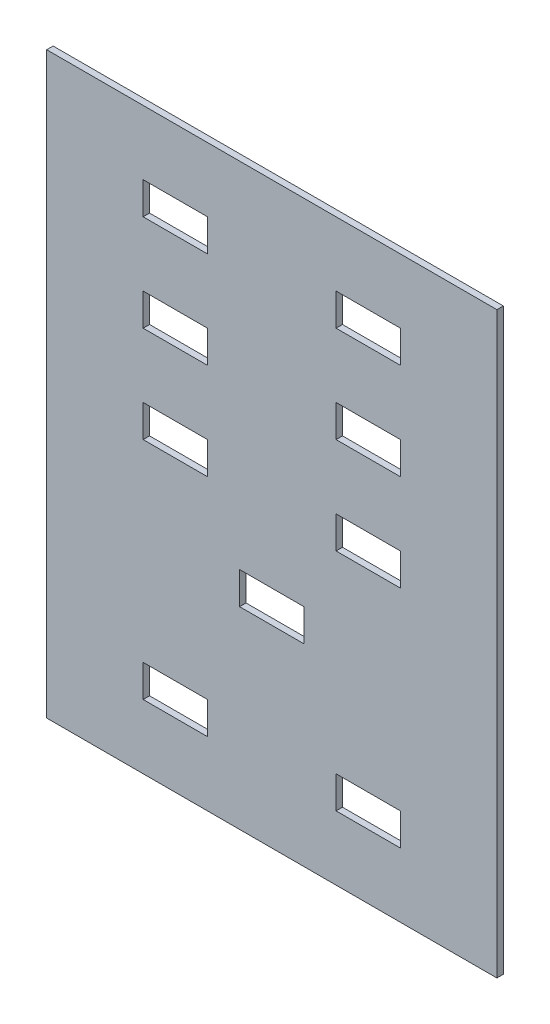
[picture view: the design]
ISO-10303-21;
HEADER;
FILE_DESCRIPTION(('STEP AP214'),'2;1');
FILE_NAME('part.step','',(''),(''),'','','');
FILE_SCHEMA(('AUTOMOTIVE_DESIGN { 1 0 10303 214 1 1 1 1 }'));
ENDSEC;
DATA;
#1=APPLICATION_CONTEXT('core data for automotive mechanical design processes');
#2=APPLICATION_PROTOCOL_DEFINITION('international standard','automotive_design',2000,#1);
#3=PRODUCT_CONTEXT('',#1,'mechanical');
#4=PRODUCT('Part','Part','',(#3));
#5=PRODUCT_RELATED_PRODUCT_CATEGORY('part','',(#4));
#6=PRODUCT_DEFINITION_FORMATION('','',#4);
#7=PRODUCT_DEFINITION_CONTEXT('part definition',#1,'design');
#8=PRODUCT_DEFINITION('design','',#6,#7);
#9=PRODUCT_DEFINITION_SHAPE('','',#8);
#10=(LENGTH_UNIT() NAMED_UNIT(*) SI_UNIT(.MILLI.,.METRE.));
#11=(NAMED_UNIT(*) PLANE_ANGLE_UNIT() SI_UNIT($,.RADIAN.));
#12=(NAMED_UNIT(*) SI_UNIT($,.STERADIAN.) SOLID_ANGLE_UNIT());
#13=UNCERTAINTY_MEASURE_WITH_UNIT(LENGTH_MEASURE(1.E-05),#10,'distance_accuracy_value','');
#14=(GEOMETRIC_REPRESENTATION_CONTEXT(3) GLOBAL_UNCERTAINTY_ASSIGNED_CONTEXT((#13)) GLOBAL_UNIT_ASSIGNED_CONTEXT((#10,
#11,#12)) REPRESENTATION_CONTEXT('',''));
#15=CARTESIAN_POINT('',(0.,0.,0.));
#16=DIRECTION('',(0.,0.,1.));
#17=DIRECTION('',(1.,0.,0.));
#18=AXIS2_PLACEMENT_3D('',#15,#16,#17);
#19=CARTESIAN_POINT('',(0.,0.,5.));
#20=DIRECTION('',(1.,0.,0.));
#21=DIRECTION('',(0.,0.,-1.));
#22=AXIS2_PLACEMENT_3D('',#19,#20,#21);
#23=PLANE('',#22);
#24=DIRECTION('',(0.,-1.,0.));
#25=VECTOR('',#24,1.);
#26=CARTESIAN_POINT('',(0.,0.,0.));
#27=LINE('',#26,#25);
#28=CARTESIAN_POINT('',(0.,450.,0.));
#29=VERTEX_POINT('',#28);
#30=CARTESIAN_POINT('',(0.,0.,0.));
#31=VERTEX_POINT('',#30);
#32=EDGE_CURVE('E576',#29,#31,#27,.T.);
#33=ORIENTED_EDGE('',*,*,#32,.T.);
#34=DIRECTION('',(0.,0.,-1.));
#35=VECTOR('',#34,1.);
#36=CARTESIAN_POINT('',(0.,0.,5.));
#37=LINE('',#36,#35);
#38=CARTESIAN_POINT('',(0.,0.,5.));
#39=VERTEX_POINT('',#38);
#40=EDGE_CURVE('E11',#39,#31,#37,.T.);
#41=ORIENTED_EDGE('',*,*,#40,.F.);
#42=DIRECTION('',(0.,-1.,0.));
#43=VECTOR('',#42,1.);
#44=CARTESIAN_POINT('',(0.,0.,5.));
#45=LINE('',#44,#43);
#46=CARTESIAN_POINT('',(0.,450.,5.));
#47=VERTEX_POINT('',#46);
#48=EDGE_CURVE('E583',#47,#39,#45,.T.);
#49=ORIENTED_EDGE('',*,*,#48,.F.);
#50=DIRECTION('',(0.,0.,-1.));
#51=VECTOR('',#50,1.);
#52=CARTESIAN_POINT('',(0.,450.,5.));
#53=LINE('',#52,#51);
#54=EDGE_CURVE('E593',#47,#29,#53,.T.);
#55=ORIENTED_EDGE('',*,*,#54,.T.);
#56=EDGE_LOOP('',(#33,#41,#49,#55));
#57=FACE_BOUND('',#56,.T.);
#58=ADVANCED_FACE('F34',(#57),#23,.F.);
#59=CARTESIAN_POINT('',(0.,0.,5.));
#60=DIRECTION('',(0.,1.,0.));
#61=DIRECTION('',(0.,0.,1.));
#62=AXIS2_PLACEMENT_3D('',#59,#60,#61);
#63=PLANE('',#62);
#64=DIRECTION('',(1.,0.,0.));
#65=VECTOR('',#64,1.);
#66=CARTESIAN_POINT('',(0.,0.,0.));
#67=LINE('',#66,#65);
#68=CARTESIAN_POINT('',(350.,0.,0.));
#69=VERTEX_POINT('',#68);
#70=EDGE_CURVE('E596',#31,#69,#67,.T.);
#71=ORIENTED_EDGE('',*,*,#70,.T.);
#72=DIRECTION('',(0.,0.,-1.));
#73=VECTOR('',#72,1.);
#74=CARTESIAN_POINT('',(350.,0.,5.));
#75=LINE('',#74,#73);
#76=CARTESIAN_POINT('',(350.,0.,5.));
#77=VERTEX_POINT('',#76);
#78=EDGE_CURVE('E41',#77,#69,#75,.T.);
#79=ORIENTED_EDGE('',*,*,#78,.F.);
#80=DIRECTION('',(1.,0.,0.));
#81=VECTOR('',#80,1.);
#82=CARTESIAN_POINT('',(0.,0.,5.));
#83=LINE('',#82,#81);
#84=EDGE_CURVE('E586',#39,#77,#83,.T.);
#85=ORIENTED_EDGE('',*,*,#84,.F.);
#86=ORIENTED_EDGE('',*,*,#40,.T.);
#87=EDGE_LOOP('',(#71,#79,#85,#86));
#88=FACE_BOUND('',#87,.T.);
#89=ADVANCED_FACE('F625',(#88),#63,.F.);
#90=CARTESIAN_POINT('',(350.,0.,5.));
#91=DIRECTION('',(-1.,0.,0.));
#92=DIRECTION('',(0.,0.,1.));
#93=AXIS2_PLACEMENT_3D('',#90,#91,#92);
#94=PLANE('',#93);
#95=DIRECTION('',(0.,1.,0.));
#96=VECTOR('',#95,1.);
#97=CARTESIAN_POINT('',(350.,0.,0.));
#98=LINE('',#97,#96);
#99=CARTESIAN_POINT('',(350.,450.,0.));
#100=VERTEX_POINT('',#99);
#101=EDGE_CURVE('E598',#69,#100,#98,.T.);
#102=ORIENTED_EDGE('',*,*,#101,.T.);
#103=DIRECTION('',(0.,0.,-1.));
#104=VECTOR('',#103,1.);
#105=CARTESIAN_POINT('',(350.,450.,5.));
#106=LINE('',#105,#104);
#107=CARTESIAN_POINT('',(350.,450.,5.));
#108=VERTEX_POINT('',#107);
#109=EDGE_CURVE('E603',#108,#100,#106,.T.);
#110=ORIENTED_EDGE('',*,*,#109,.F.);
#111=DIRECTION('',(0.,1.,0.));
#112=VECTOR('',#111,1.);
#113=CARTESIAN_POINT('',(350.,0.,5.));
#114=LINE('',#113,#112);
#115=EDGE_CURVE('E589',#77,#108,#114,.T.);
#116=ORIENTED_EDGE('',*,*,#115,.F.);
#117=ORIENTED_EDGE('',*,*,#78,.T.);
#118=EDGE_LOOP('',(#102,#110,#116,#117));
#119=FACE_BOUND('',#118,.T.);
#120=ADVANCED_FACE('F610',(#119),#94,.F.);
#121=CARTESIAN_POINT('',(0.,450.,5.));
#122=DIRECTION('',(0.,-1.,0.));
#123=DIRECTION('',(0.,0.,-1.));
#124=AXIS2_PLACEMENT_3D('',#121,#122,#123);
#125=PLANE('',#124);
#126=DIRECTION('',(-1.,0.,0.));
#127=VECTOR('',#126,1.);
#128=CARTESIAN_POINT('',(0.,450.,0.));
#129=LINE('',#128,#127);
#130=EDGE_CURVE('E587',#100,#29,#129,.T.);
#131=ORIENTED_EDGE('',*,*,#130,.T.);
#132=ORIENTED_EDGE('',*,*,#54,.F.);
#133=DIRECTION('',(-1.,0.,0.));
#134=VECTOR('',#133,1.);
#135=CARTESIAN_POINT('',(0.,450.,5.));
#136=LINE('',#135,#134);
#137=EDGE_CURVE('E591',#108,#47,#136,.T.);
#138=ORIENTED_EDGE('',*,*,#137,.F.);
#139=ORIENTED_EDGE('',*,*,#109,.T.);
#140=EDGE_LOOP('',(#131,#132,#138,#139));
#141=FACE_BOUND('',#140,.T.);
#142=ADVANCED_FACE('F618',(#141),#125,.F.);
#143=CARTESIAN_POINT('',(0.,0.,5.));
#144=DIRECTION('',(0.,0.,-1.));
#145=DIRECTION('',(-1.,0.,0.));
#146=AXIS2_PLACEMENT_3D('',#143,#144,#145);
#147=PLANE('',#146);
#148=DIRECTION('',(-1.,0.,0.));
#149=VECTOR('',#148,1.);
#150=CARTESIAN_POINT('',(225.,75.,5.));
#151=LINE('',#150,#149);
#152=CARTESIAN_POINT('',(275.,75.,5.));
#153=VERTEX_POINT('',#152);
#154=CARTESIAN_POINT('',(225.,75.,5.));
#155=VERTEX_POINT('',#154);
#156=EDGE_CURVE('E317',#153,#155,#151,.T.);
#157=ORIENTED_EDGE('',*,*,#156,.F.);
#158=DIRECTION('',(0.,1.,0.));
#159=VECTOR('',#158,1.);
#160=CARTESIAN_POINT('',(275.,49.9999999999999,5.));
#161=LINE('',#160,#159);
#162=CARTESIAN_POINT('',(275.,49.9999999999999,5.));
#163=VERTEX_POINT('',#162);
#164=EDGE_CURVE('E48',#163,#153,#161,.T.);
#165=ORIENTED_EDGE('',*,*,#164,.F.);
#166=DIRECTION('',(1.,0.,0.));
#167=VECTOR('',#166,1.);
#168=CARTESIAN_POINT('',(225.,49.9999999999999,5.));
#169=LINE('',#168,#167);
#170=CARTESIAN_POINT('',(225.,49.9999999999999,5.));
#171=VERTEX_POINT('',#170);
#172=EDGE_CURVE('E308',#171,#163,#169,.T.);
#173=ORIENTED_EDGE('',*,*,#172,.F.);
#174=DIRECTION('',(0.,-1.,0.));
#175=VECTOR('',#174,1.);
#176=CARTESIAN_POINT('',(225.,49.9999999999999,5.));
#177=LINE('',#176,#175);
#178=EDGE_CURVE('E311',#155,#171,#177,.T.);
#179=ORIENTED_EDGE('',*,*,#178,.F.);
#180=EDGE_LOOP('',(#157,#165,#173,#179));
#181=FACE_BOUND('',#180,.T.);
#182=DIRECTION('',(-1.,0.,0.));
#183=VECTOR('',#182,1.);
#184=CARTESIAN_POINT('',(75.0000000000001,75.,5.));
#185=LINE('',#184,#183);
#186=CARTESIAN_POINT('',(125.,75.,5.));
#187=VERTEX_POINT('',#186);
#188=CARTESIAN_POINT('',(75.0000000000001,75.,5.));
#189=VERTEX_POINT('',#188);
#190=EDGE_CURVE('E342',#187,#189,#185,.T.);
#191=ORIENTED_EDGE('',*,*,#190,.F.);
#192=DIRECTION('',(0.,1.,0.));
#193=VECTOR('',#192,1.);
#194=CARTESIAN_POINT('',(125.,49.9999999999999,5.));
#195=LINE('',#194,#193);
#196=CARTESIAN_POINT('',(125.,49.9999999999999,5.));
#197=VERTEX_POINT('',#196);
#198=EDGE_CURVE('E323',#197,#187,#195,.T.);
#199=ORIENTED_EDGE('',*,*,#198,.F.);
#200=DIRECTION('',(1.,0.,0.));
#201=VECTOR('',#200,1.);
#202=CARTESIAN_POINT('',(75.0000000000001,49.9999999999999,5.));
#203=LINE('',#202,#201);
#204=CARTESIAN_POINT('',(75.0000000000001,49.9999999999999,5.));
#205=VERTEX_POINT('',#204);
#206=EDGE_CURVE('E331',#205,#197,#203,.T.);
#207=ORIENTED_EDGE('',*,*,#206,.F.);
#208=DIRECTION('',(0.,-1.,0.));
#209=VECTOR('',#208,1.);
#210=CARTESIAN_POINT('',(75.0000000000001,49.9999999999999,5.));
#211=LINE('',#210,#209);
#212=EDGE_CURVE('E345',#189,#205,#211,.T.);
#213=ORIENTED_EDGE('',*,*,#212,.F.);
#214=EDGE_LOOP('',(#191,#199,#207,#213));
#215=FACE_BOUND('',#214,.T.);
#216=DIRECTION('',(-1.,0.,0.));
#217=VECTOR('',#216,1.);
#218=CARTESIAN_POINT('',(150.,175.,5.));
#219=LINE('',#218,#217);
#220=CARTESIAN_POINT('',(200.,175.,5.));
#221=VERTEX_POINT('',#220);
#222=CARTESIAN_POINT('',(150.,175.,5.));
#223=VERTEX_POINT('',#222);
#224=EDGE_CURVE('E374',#221,#223,#219,.T.);
#225=ORIENTED_EDGE('',*,*,#224,.F.);
#226=DIRECTION('',(0.,1.,0.));
#227=VECTOR('',#226,1.);
#228=CARTESIAN_POINT('',(200.,150.,5.));
#229=LINE('',#228,#227);
#230=CARTESIAN_POINT('',(200.,150.,5.));
#231=VERTEX_POINT('',#230);
#232=EDGE_CURVE('E352',#231,#221,#229,.T.);
#233=ORIENTED_EDGE('',*,*,#232,.F.);
#234=DIRECTION('',(1.,0.,0.));
#235=VECTOR('',#234,1.);
#236=CARTESIAN_POINT('',(150.,150.,5.));
#237=LINE('',#236,#235);
#238=CARTESIAN_POINT('',(150.,150.,5.));
#239=VERTEX_POINT('',#238);
#240=EDGE_CURVE('E363',#239,#231,#237,.T.);
#241=ORIENTED_EDGE('',*,*,#240,.F.);
#242=DIRECTION('',(0.,-1.,0.));
#243=VECTOR('',#242,1.);
#244=CARTESIAN_POINT('',(150.,150.,5.));
#245=LINE('',#244,#243);
#246=EDGE_CURVE('E377',#223,#239,#245,.T.);
#247=ORIENTED_EDGE('',*,*,#246,.F.);
#248=EDGE_LOOP('',(#225,#233,#241,#247));
#249=FACE_BOUND('',#248,.T.);
#250=DIRECTION('',(-1.,0.,0.));
#251=VECTOR('',#250,1.);
#252=CARTESIAN_POINT('',(225.,250.,5.));
#253=LINE('',#252,#251);
#254=CARTESIAN_POINT('',(275.,250.,5.));
#255=VERTEX_POINT('',#254);
#256=CARTESIAN_POINT('',(225.,250.,5.));
#257=VERTEX_POINT('',#256);
#258=EDGE_CURVE('E406',#255,#257,#253,.T.);
#259=ORIENTED_EDGE('',*,*,#258,.F.);
#260=DIRECTION('',(0.,1.,0.));
#261=VECTOR('',#260,1.);
#262=CARTESIAN_POINT('',(275.,225.,5.));
#263=LINE('',#262,#261);
#264=CARTESIAN_POINT('',(275.,225.,5.));
#265=VERTEX_POINT('',#264);
#266=EDGE_CURVE('E384',#265,#255,#263,.T.);
#267=ORIENTED_EDGE('',*,*,#266,.F.);
#268=DIRECTION('',(1.,0.,0.));
#269=VECTOR('',#268,1.);
#270=CARTESIAN_POINT('',(225.,225.,5.));
#271=LINE('',#270,#269);
#272=CARTESIAN_POINT('',(225.,225.,5.));
#273=VERTEX_POINT('',#272);
#274=EDGE_CURVE('E395',#273,#265,#271,.T.);
#275=ORIENTED_EDGE('',*,*,#274,.F.);
#276=DIRECTION('',(0.,-1.,0.));
#277=VECTOR('',#276,1.);
#278=CARTESIAN_POINT('',(225.,225.,5.));
#279=LINE('',#278,#277);
#280=EDGE_CURVE('E409',#257,#273,#279,.T.);
#281=ORIENTED_EDGE('',*,*,#280,.F.);
#282=EDGE_LOOP('',(#259,#267,#275,#281));
#283=FACE_BOUND('',#282,.T.);
#284=DIRECTION('',(-1.,0.,0.));
#285=VECTOR('',#284,1.);
#286=CARTESIAN_POINT('',(75.0000000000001,250.,5.));
#287=LINE('',#286,#285);
#288=CARTESIAN_POINT('',(125.,250.,5.));
#289=VERTEX_POINT('',#288);
#290=CARTESIAN_POINT('',(75.0000000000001,250.,5.));
#291=VERTEX_POINT('',#290);
#292=EDGE_CURVE('E438',#289,#291,#287,.T.);
#293=ORIENTED_EDGE('',*,*,#292,.F.);
#294=DIRECTION('',(0.,1.,0.));
#295=VECTOR('',#294,1.);
#296=CARTESIAN_POINT('',(125.,225.,5.));
#297=LINE('',#296,#295);
#298=CARTESIAN_POINT('',(125.,225.,5.));
#299=VERTEX_POINT('',#298);
#300=EDGE_CURVE('E416',#299,#289,#297,.T.);
#301=ORIENTED_EDGE('',*,*,#300,.F.);
#302=DIRECTION('',(1.,0.,0.));
#303=VECTOR('',#302,1.);
#304=CARTESIAN_POINT('',(75.0000000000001,225.,5.));
#305=LINE('',#304,#303);
#306=CARTESIAN_POINT('',(75.0000000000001,225.,5.));
#307=VERTEX_POINT('',#306);
#308=EDGE_CURVE('E427',#307,#299,#305,.T.);
#309=ORIENTED_EDGE('',*,*,#308,.F.);
#310=DIRECTION('',(0.,-1.,0.));
#311=VECTOR('',#310,1.);
#312=CARTESIAN_POINT('',(75.0000000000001,225.,5.));
#313=LINE('',#312,#311);
#314=EDGE_CURVE('E441',#291,#307,#313,.T.);
#315=ORIENTED_EDGE('',*,*,#314,.F.);
#316=EDGE_LOOP('',(#293,#301,#309,#315));
#317=FACE_BOUND('',#316,.T.);
#318=DIRECTION('',(-1.,0.,0.));
#319=VECTOR('',#318,1.);
#320=CARTESIAN_POINT('',(75.,325.,5.));
#321=LINE('',#320,#319);
#322=CARTESIAN_POINT('',(125.,325.,5.));
#323=VERTEX_POINT('',#322);
#324=CARTESIAN_POINT('',(75.,325.,5.));
#325=VERTEX_POINT('',#324);
#326=EDGE_CURVE('E470',#323,#325,#321,.T.);
#327=ORIENTED_EDGE('',*,*,#326,.F.);
#328=DIRECTION('',(0.,1.,0.));
#329=VECTOR('',#328,1.);
#330=CARTESIAN_POINT('',(125.,300.,5.));
#331=LINE('',#330,#329);
#332=CARTESIAN_POINT('',(125.,300.,5.));
#333=VERTEX_POINT('',#332);
#334=EDGE_CURVE('E448',#333,#323,#331,.T.);
#335=ORIENTED_EDGE('',*,*,#334,.F.);
#336=DIRECTION('',(1.,0.,0.));
#337=VECTOR('',#336,1.);
#338=CARTESIAN_POINT('',(75.,300.,5.));
#339=LINE('',#338,#337);
#340=CARTESIAN_POINT('',(75.,300.,5.));
#341=VERTEX_POINT('',#340);
#342=EDGE_CURVE('E459',#341,#333,#339,.T.);
#343=ORIENTED_EDGE('',*,*,#342,.F.);
#344=DIRECTION('',(0.,-1.,0.));
#345=VECTOR('',#344,1.);
#346=CARTESIAN_POINT('',(75.,300.,5.));
#347=LINE('',#346,#345);
#348=EDGE_CURVE('E473',#325,#341,#347,.T.);
#349=ORIENTED_EDGE('',*,*,#348,.F.);
#350=EDGE_LOOP('',(#327,#335,#343,#349));
#351=FACE_BOUND('',#350,.T.);
#352=DIRECTION('',(-1.,0.,0.));
#353=VECTOR('',#352,1.);
#354=CARTESIAN_POINT('',(225.,325.,5.));
#355=LINE('',#354,#353);
#356=CARTESIAN_POINT('',(275.,325.,5.));
#357=VERTEX_POINT('',#356);
#358=CARTESIAN_POINT('',(225.,325.,5.));
#359=VERTEX_POINT('',#358);
#360=EDGE_CURVE('E502',#357,#359,#355,.T.);
#361=ORIENTED_EDGE('',*,*,#360,.F.);
#362=DIRECTION('',(0.,1.,0.));
#363=VECTOR('',#362,1.);
#364=CARTESIAN_POINT('',(275.,300.,5.));
#365=LINE('',#364,#363);
#366=CARTESIAN_POINT('',(275.,300.,5.));
#367=VERTEX_POINT('',#366);
#368=EDGE_CURVE('E480',#367,#357,#365,.T.);
#369=ORIENTED_EDGE('',*,*,#368,.F.);
#370=DIRECTION('',(1.,0.,0.));
#371=VECTOR('',#370,1.);
#372=CARTESIAN_POINT('',(225.,300.,5.));
#373=LINE('',#372,#371);
#374=CARTESIAN_POINT('',(225.,300.,5.));
#375=VERTEX_POINT('',#374);
#376=EDGE_CURVE('E491',#375,#367,#373,.T.);
#377=ORIENTED_EDGE('',*,*,#376,.F.);
#378=DIRECTION('',(0.,-1.,0.));
#379=VECTOR('',#378,1.);
#380=CARTESIAN_POINT('',(225.,300.,5.));
#381=LINE('',#380,#379);
#382=EDGE_CURVE('E505',#359,#375,#381,.T.);
#383=ORIENTED_EDGE('',*,*,#382,.F.);
#384=EDGE_LOOP('',(#361,#369,#377,#383));
#385=FACE_BOUND('',#384,.T.);
#386=DIRECTION('',(-1.,0.,0.));
#387=VECTOR('',#386,1.);
#388=CARTESIAN_POINT('',(225.,400.,5.));
#389=LINE('',#388,#387);
#390=CARTESIAN_POINT('',(275.,400.,5.));
#391=VERTEX_POINT('',#390);
#392=CARTESIAN_POINT('',(225.,400.,5.));
#393=VERTEX_POINT('',#392);
#394=EDGE_CURVE('E534',#391,#393,#389,.T.);
#395=ORIENTED_EDGE('',*,*,#394,.F.);
#396=DIRECTION('',(0.,1.,0.));
#397=VECTOR('',#396,1.);
#398=CARTESIAN_POINT('',(275.,375.,5.));
#399=LINE('',#398,#397);
#400=CARTESIAN_POINT('',(275.,375.,5.));
#401=VERTEX_POINT('',#400);
#402=EDGE_CURVE('E512',#401,#391,#399,.T.);
#403=ORIENTED_EDGE('',*,*,#402,.F.);
#404=DIRECTION('',(1.,0.,0.));
#405=VECTOR('',#404,1.);
#406=CARTESIAN_POINT('',(225.,375.,5.));
#407=LINE('',#406,#405);
#408=CARTESIAN_POINT('',(225.,375.,5.));
#409=VERTEX_POINT('',#408);
#410=EDGE_CURVE('E523',#409,#401,#407,.T.);
#411=ORIENTED_EDGE('',*,*,#410,.F.);
#412=DIRECTION('',(0.,-1.,0.));
#413=VECTOR('',#412,1.);
#414=CARTESIAN_POINT('',(225.,375.,5.));
#415=LINE('',#414,#413);
#416=EDGE_CURVE('E537',#393,#409,#415,.T.);
#417=ORIENTED_EDGE('',*,*,#416,.F.);
#418=EDGE_LOOP('',(#395,#403,#411,#417));
#419=FACE_BOUND('',#418,.T.);
#420=DIRECTION('',(-1.,0.,0.));
#421=VECTOR('',#420,1.);
#422=CARTESIAN_POINT('',(75.,400.,5.));
#423=LINE('',#422,#421);
#424=CARTESIAN_POINT('',(125.,400.,5.));
#425=VERTEX_POINT('',#424);
#426=CARTESIAN_POINT('',(75.,400.,5.));
#427=VERTEX_POINT('',#426);
#428=EDGE_CURVE('E566',#425,#427,#423,.T.);
#429=ORIENTED_EDGE('',*,*,#428,.F.);
#430=DIRECTION('',(0.,1.,0.));
#431=VECTOR('',#430,1.);
#432=CARTESIAN_POINT('',(125.,375.,5.));
#433=LINE('',#432,#431);
#434=CARTESIAN_POINT('',(125.,375.,5.));
#435=VERTEX_POINT('',#434);
#436=EDGE_CURVE('E544',#435,#425,#433,.T.);
#437=ORIENTED_EDGE('',*,*,#436,.F.);
#438=DIRECTION('',(1.,0.,0.));
#439=VECTOR('',#438,1.);
#440=CARTESIAN_POINT('',(75.,375.,5.));
#441=LINE('',#440,#439);
#442=CARTESIAN_POINT('',(75.,375.,5.));
#443=VERTEX_POINT('',#442);
#444=EDGE_CURVE('E555',#443,#435,#441,.T.);
#445=ORIENTED_EDGE('',*,*,#444,.F.);
#446=DIRECTION('',(0.,-1.,0.));
#447=VECTOR('',#446,1.);
#448=CARTESIAN_POINT('',(75.,375.,5.));
#449=LINE('',#448,#447);
#450=EDGE_CURVE('E569',#427,#443,#449,.T.);
#451=ORIENTED_EDGE('',*,*,#450,.F.);
#452=EDGE_LOOP('',(#429,#437,#445,#451));
#453=FACE_BOUND('',#452,.T.);
#454=ORIENTED_EDGE('',*,*,#48,.T.);
#455=ORIENTED_EDGE('',*,*,#84,.T.);
#456=ORIENTED_EDGE('',*,*,#115,.T.);
#457=ORIENTED_EDGE('',*,*,#137,.T.);
#458=EDGE_LOOP('',(#454,#455,#456,#457));
#459=FACE_BOUND('',#458,.T.);
#460=ADVANCED_FACE('F624',(#181,#215,#249,#283,#317,#351,#385,#419,#453,#459),#147,.F.);
#461=CARTESIAN_POINT('',(0.,0.,0.));
#462=DIRECTION('',(0.,0.,-1.));
#463=DIRECTION('',(-1.,0.,0.));
#464=AXIS2_PLACEMENT_3D('',#461,#462,#463);
#465=PLANE('',#464);
#466=DIRECTION('',(0.,1.,0.));
#467=VECTOR('',#466,1.);
#468=CARTESIAN_POINT('',(275.,49.9999999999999,0.));
#469=LINE('',#468,#467);
#470=CARTESIAN_POINT('',(275.,49.9999999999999,0.));
#471=VERTEX_POINT('',#470);
#472=CARTESIAN_POINT('',(275.,75.,0.));
#473=VERTEX_POINT('',#472);
#474=EDGE_CURVE('E292',#471,#473,#469,.T.);
#475=ORIENTED_EDGE('',*,*,#474,.T.);
#476=DIRECTION('',(-1.,0.,0.));
#477=VECTOR('',#476,1.);
#478=CARTESIAN_POINT('',(225.,75.,0.));
#479=LINE('',#478,#477);
#480=CARTESIAN_POINT('',(225.,75.,0.));
#481=VERTEX_POINT('',#480);
#482=EDGE_CURVE('E301',#473,#481,#479,.T.);
#483=ORIENTED_EDGE('',*,*,#482,.T.);
#484=DIRECTION('',(0.,-1.,0.));
#485=VECTOR('',#484,1.);
#486=CARTESIAN_POINT('',(225.,49.9999999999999,0.));
#487=LINE('',#486,#485);
#488=CARTESIAN_POINT('',(225.,49.9999999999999,0.));
#489=VERTEX_POINT('',#488);
#490=EDGE_CURVE('E56',#481,#489,#487,.T.);
#491=ORIENTED_EDGE('',*,*,#490,.T.);
#492=DIRECTION('',(1.,0.,0.));
#493=VECTOR('',#492,1.);
#494=CARTESIAN_POINT('',(225.,49.9999999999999,0.));
#495=LINE('',#494,#493);
#496=EDGE_CURVE('E298',#489,#471,#495,.T.);
#497=ORIENTED_EDGE('',*,*,#496,.T.);
#498=EDGE_LOOP('',(#475,#483,#491,#497));
#499=FACE_BOUND('',#498,.T.);
#500=DIRECTION('',(0.,1.,0.));
#501=VECTOR('',#500,1.);
#502=CARTESIAN_POINT('',(125.,49.9999999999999,0.));
#503=LINE('',#502,#501);
#504=CARTESIAN_POINT('',(125.,49.9999999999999,0.));
#505=VERTEX_POINT('',#504);
#506=CARTESIAN_POINT('',(125.,75.,0.));
#507=VERTEX_POINT('',#506);
#508=EDGE_CURVE('E327',#505,#507,#503,.T.);
#509=ORIENTED_EDGE('',*,*,#508,.T.);
#510=DIRECTION('',(-1.,0.,0.));
#511=VECTOR('',#510,1.);
#512=CARTESIAN_POINT('',(75.0000000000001,75.,0.));
#513=LINE('',#512,#511);
#514=CARTESIAN_POINT('',(75.0000000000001,75.,0.));
#515=VERTEX_POINT('',#514);
#516=EDGE_CURVE('E330',#507,#515,#513,.T.);
#517=ORIENTED_EDGE('',*,*,#516,.T.);
#518=DIRECTION('',(0.,-1.,0.));
#519=VECTOR('',#518,1.);
#520=CARTESIAN_POINT('',(75.0000000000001,49.9999999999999,0.));
#521=LINE('',#520,#519);
#522=CARTESIAN_POINT('',(75.0000000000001,49.9999999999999,0.));
#523=VERTEX_POINT('',#522);
#524=EDGE_CURVE('E334',#515,#523,#521,.T.);
#525=ORIENTED_EDGE('',*,*,#524,.T.);
#526=DIRECTION('',(1.,0.,0.));
#527=VECTOR('',#526,1.);
#528=CARTESIAN_POINT('',(75.0000000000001,49.9999999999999,0.));
#529=LINE('',#528,#527);
#530=EDGE_CURVE('E337',#523,#505,#529,.T.);
#531=ORIENTED_EDGE('',*,*,#530,.T.);
#532=EDGE_LOOP('',(#509,#517,#525,#531));
#533=FACE_BOUND('',#532,.T.);
#534=DIRECTION('',(0.,1.,0.));
#535=VECTOR('',#534,1.);
#536=CARTESIAN_POINT('',(200.,150.,0.));
#537=LINE('',#536,#535);
#538=CARTESIAN_POINT('',(200.,150.,0.));
#539=VERTEX_POINT('',#538);
#540=CARTESIAN_POINT('',(200.,175.,0.));
#541=VERTEX_POINT('',#540);
#542=EDGE_CURVE('E359',#539,#541,#537,.T.);
#543=ORIENTED_EDGE('',*,*,#542,.T.);
#544=DIRECTION('',(-1.,0.,0.));
#545=VECTOR('',#544,1.);
#546=CARTESIAN_POINT('',(150.,175.,0.));
#547=LINE('',#546,#545);
#548=CARTESIAN_POINT('',(150.,175.,0.));
#549=VERTEX_POINT('',#548);
#550=EDGE_CURVE('E362',#541,#549,#547,.T.);
#551=ORIENTED_EDGE('',*,*,#550,.T.);
#552=DIRECTION('',(0.,-1.,0.));
#553=VECTOR('',#552,1.);
#554=CARTESIAN_POINT('',(150.,150.,0.));
#555=LINE('',#554,#553);
#556=CARTESIAN_POINT('',(150.,150.,0.));
#557=VERTEX_POINT('',#556);
#558=EDGE_CURVE('E366',#549,#557,#555,.T.);
#559=ORIENTED_EDGE('',*,*,#558,.T.);
#560=DIRECTION('',(1.,0.,0.));
#561=VECTOR('',#560,1.);
#562=CARTESIAN_POINT('',(150.,150.,0.));
#563=LINE('',#562,#561);
#564=EDGE_CURVE('E369',#557,#539,#563,.T.);
#565=ORIENTED_EDGE('',*,*,#564,.T.);
#566=EDGE_LOOP('',(#543,#551,#559,#565));
#567=FACE_BOUND('',#566,.T.);
#568=DIRECTION('',(0.,1.,0.));
#569=VECTOR('',#568,1.);
#570=CARTESIAN_POINT('',(275.,225.,0.));
#571=LINE('',#570,#569);
#572=CARTESIAN_POINT('',(275.,225.,0.));
#573=VERTEX_POINT('',#572);
#574=CARTESIAN_POINT('',(275.,250.,0.));
#575=VERTEX_POINT('',#574);
#576=EDGE_CURVE('E391',#573,#575,#571,.T.);
#577=ORIENTED_EDGE('',*,*,#576,.T.);
#578=DIRECTION('',(-1.,0.,0.));
#579=VECTOR('',#578,1.);
#580=CARTESIAN_POINT('',(225.,250.,0.));
#581=LINE('',#580,#579);
#582=CARTESIAN_POINT('',(225.,250.,0.));
#583=VERTEX_POINT('',#582);
#584=EDGE_CURVE('E394',#575,#583,#581,.T.);
#585=ORIENTED_EDGE('',*,*,#584,.T.);
#586=DIRECTION('',(0.,-1.,0.));
#587=VECTOR('',#586,1.);
#588=CARTESIAN_POINT('',(225.,225.,0.));
#589=LINE('',#588,#587);
#590=CARTESIAN_POINT('',(225.,225.,0.));
#591=VERTEX_POINT('',#590);
#592=EDGE_CURVE('E398',#583,#591,#589,.T.);
#593=ORIENTED_EDGE('',*,*,#592,.T.);
#594=DIRECTION('',(1.,0.,0.));
#595=VECTOR('',#594,1.);
#596=CARTESIAN_POINT('',(225.,225.,0.));
#597=LINE('',#596,#595);
#598=EDGE_CURVE('E401',#591,#573,#597,.T.);
#599=ORIENTED_EDGE('',*,*,#598,.T.);
#600=EDGE_LOOP('',(#577,#585,#593,#599));
#601=FACE_BOUND('',#600,.T.);
#602=DIRECTION('',(0.,1.,0.));
#603=VECTOR('',#602,1.);
#604=CARTESIAN_POINT('',(125.,225.,0.));
#605=LINE('',#604,#603);
#606=CARTESIAN_POINT('',(125.,225.,0.));
#607=VERTEX_POINT('',#606);
#608=CARTESIAN_POINT('',(125.,250.,0.));
#609=VERTEX_POINT('',#608);
#610=EDGE_CURVE('E423',#607,#609,#605,.T.);
#611=ORIENTED_EDGE('',*,*,#610,.T.);
#612=DIRECTION('',(-1.,0.,0.));
#613=VECTOR('',#612,1.);
#614=CARTESIAN_POINT('',(75.0000000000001,250.,0.));
#615=LINE('',#614,#613);
#616=CARTESIAN_POINT('',(75.0000000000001,250.,0.));
#617=VERTEX_POINT('',#616);
#618=EDGE_CURVE('E426',#609,#617,#615,.T.);
#619=ORIENTED_EDGE('',*,*,#618,.T.);
#620=DIRECTION('',(0.,-1.,0.));
#621=VECTOR('',#620,1.);
#622=CARTESIAN_POINT('',(75.0000000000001,225.,0.));
#623=LINE('',#622,#621);
#624=CARTESIAN_POINT('',(75.0000000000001,225.,0.));
#625=VERTEX_POINT('',#624);
#626=EDGE_CURVE('E430',#617,#625,#623,.T.);
#627=ORIENTED_EDGE('',*,*,#626,.T.);
#628=DIRECTION('',(1.,0.,0.));
#629=VECTOR('',#628,1.);
#630=CARTESIAN_POINT('',(75.0000000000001,225.,0.));
#631=LINE('',#630,#629);
#632=EDGE_CURVE('E433',#625,#607,#631,.T.);
#633=ORIENTED_EDGE('',*,*,#632,.T.);
#634=EDGE_LOOP('',(#611,#619,#627,#633));
#635=FACE_BOUND('',#634,.T.);
#636=DIRECTION('',(0.,1.,0.));
#637=VECTOR('',#636,1.);
#638=CARTESIAN_POINT('',(125.,300.,0.));
#639=LINE('',#638,#637);
#640=CARTESIAN_POINT('',(125.,300.,0.));
#641=VERTEX_POINT('',#640);
#642=CARTESIAN_POINT('',(125.,325.,0.));
#643=VERTEX_POINT('',#642);
#644=EDGE_CURVE('E455',#641,#643,#639,.T.);
#645=ORIENTED_EDGE('',*,*,#644,.T.);
#646=DIRECTION('',(-1.,0.,0.));
#647=VECTOR('',#646,1.);
#648=CARTESIAN_POINT('',(75.,325.,0.));
#649=LINE('',#648,#647);
#650=CARTESIAN_POINT('',(75.,325.,0.));
#651=VERTEX_POINT('',#650);
#652=EDGE_CURVE('E458',#643,#651,#649,.T.);
#653=ORIENTED_EDGE('',*,*,#652,.T.);
#654=DIRECTION('',(0.,-1.,0.));
#655=VECTOR('',#654,1.);
#656=CARTESIAN_POINT('',(75.,300.,0.));
#657=LINE('',#656,#655);
#658=CARTESIAN_POINT('',(75.,300.,0.));
#659=VERTEX_POINT('',#658);
#660=EDGE_CURVE('E462',#651,#659,#657,.T.);
#661=ORIENTED_EDGE('',*,*,#660,.T.);
#662=DIRECTION('',(1.,0.,0.));
#663=VECTOR('',#662,1.);
#664=CARTESIAN_POINT('',(75.,300.,0.));
#665=LINE('',#664,#663);
#666=EDGE_CURVE('E465',#659,#641,#665,.T.);
#667=ORIENTED_EDGE('',*,*,#666,.T.);
#668=EDGE_LOOP('',(#645,#653,#661,#667));
#669=FACE_BOUND('',#668,.T.);
#670=DIRECTION('',(0.,1.,0.));
#671=VECTOR('',#670,1.);
#672=CARTESIAN_POINT('',(275.,300.,0.));
#673=LINE('',#672,#671);
#674=CARTESIAN_POINT('',(275.,300.,0.));
#675=VERTEX_POINT('',#674);
#676=CARTESIAN_POINT('',(275.,325.,0.));
#677=VERTEX_POINT('',#676);
#678=EDGE_CURVE('E487',#675,#677,#673,.T.);
#679=ORIENTED_EDGE('',*,*,#678,.T.);
#680=DIRECTION('',(-1.,0.,0.));
#681=VECTOR('',#680,1.);
#682=CARTESIAN_POINT('',(225.,325.,0.));
#683=LINE('',#682,#681);
#684=CARTESIAN_POINT('',(225.,325.,0.));
#685=VERTEX_POINT('',#684);
#686=EDGE_CURVE('E490',#677,#685,#683,.T.);
#687=ORIENTED_EDGE('',*,*,#686,.T.);
#688=DIRECTION('',(0.,-1.,0.));
#689=VECTOR('',#688,1.);
#690=CARTESIAN_POINT('',(225.,300.,0.));
#691=LINE('',#690,#689);
#692=CARTESIAN_POINT('',(225.,300.,0.));
#693=VERTEX_POINT('',#692);
#694=EDGE_CURVE('E494',#685,#693,#691,.T.);
#695=ORIENTED_EDGE('',*,*,#694,.T.);
#696=DIRECTION('',(1.,0.,0.));
#697=VECTOR('',#696,1.);
#698=CARTESIAN_POINT('',(225.,300.,0.));
#699=LINE('',#698,#697);
#700=EDGE_CURVE('E497',#693,#675,#699,.T.);
#701=ORIENTED_EDGE('',*,*,#700,.T.);
#702=EDGE_LOOP('',(#679,#687,#695,#701));
#703=FACE_BOUND('',#702,.T.);
#704=DIRECTION('',(0.,1.,0.));
#705=VECTOR('',#704,1.);
#706=CARTESIAN_POINT('',(275.,375.,0.));
#707=LINE('',#706,#705);
#708=CARTESIAN_POINT('',(275.,375.,0.));
#709=VERTEX_POINT('',#708);
#710=CARTESIAN_POINT('',(275.,400.,0.));
#711=VERTEX_POINT('',#710);
#712=EDGE_CURVE('E519',#709,#711,#707,.T.);
#713=ORIENTED_EDGE('',*,*,#712,.T.);
#714=DIRECTION('',(-1.,0.,0.));
#715=VECTOR('',#714,1.);
#716=CARTESIAN_POINT('',(225.,400.,0.));
#717=LINE('',#716,#715);
#718=CARTESIAN_POINT('',(225.,400.,0.));
#719=VERTEX_POINT('',#718);
#720=EDGE_CURVE('E522',#711,#719,#717,.T.);
#721=ORIENTED_EDGE('',*,*,#720,.T.);
#722=DIRECTION('',(0.,-1.,0.));
#723=VECTOR('',#722,1.);
#724=CARTESIAN_POINT('',(225.,375.,0.));
#725=LINE('',#724,#723);
#726=CARTESIAN_POINT('',(225.,375.,0.));
#727=VERTEX_POINT('',#726);
#728=EDGE_CURVE('E526',#719,#727,#725,.T.);
#729=ORIENTED_EDGE('',*,*,#728,.T.);
#730=DIRECTION('',(1.,0.,0.));
#731=VECTOR('',#730,1.);
#732=CARTESIAN_POINT('',(225.,375.,0.));
#733=LINE('',#732,#731);
#734=EDGE_CURVE('E529',#727,#709,#733,.T.);
#735=ORIENTED_EDGE('',*,*,#734,.T.);
#736=EDGE_LOOP('',(#713,#721,#729,#735));
#737=FACE_BOUND('',#736,.T.);
#738=DIRECTION('',(0.,1.,0.));
#739=VECTOR('',#738,1.);
#740=CARTESIAN_POINT('',(125.,375.,0.));
#741=LINE('',#740,#739);
#742=CARTESIAN_POINT('',(125.,375.,0.));
#743=VERTEX_POINT('',#742);
#744=CARTESIAN_POINT('',(125.,400.,0.));
#745=VERTEX_POINT('',#744);
#746=EDGE_CURVE('E551',#743,#745,#741,.T.);
#747=ORIENTED_EDGE('',*,*,#746,.T.);
#748=DIRECTION('',(-1.,0.,0.));
#749=VECTOR('',#748,1.);
#750=CARTESIAN_POINT('',(75.,400.,0.));
#751=LINE('',#750,#749);
#752=CARTESIAN_POINT('',(75.,400.,0.));
#753=VERTEX_POINT('',#752);
#754=EDGE_CURVE('E554',#745,#753,#751,.T.);
#755=ORIENTED_EDGE('',*,*,#754,.T.);
#756=DIRECTION('',(0.,-1.,0.));
#757=VECTOR('',#756,1.);
#758=CARTESIAN_POINT('',(75.,375.,0.));
#759=LINE('',#758,#757);
#760=CARTESIAN_POINT('',(75.,375.,0.));
#761=VERTEX_POINT('',#760);
#762=EDGE_CURVE('E558',#753,#761,#759,.T.);
#763=ORIENTED_EDGE('',*,*,#762,.T.);
#764=DIRECTION('',(1.,0.,0.));
#765=VECTOR('',#764,1.);
#766=CARTESIAN_POINT('',(75.,375.,0.));
#767=LINE('',#766,#765);
#768=EDGE_CURVE('E561',#761,#743,#767,.T.);
#769=ORIENTED_EDGE('',*,*,#768,.T.);
#770=EDGE_LOOP('',(#747,#755,#763,#769));
#771=FACE_BOUND('',#770,.T.);
#772=ORIENTED_EDGE('',*,*,#32,.F.);
#773=ORIENTED_EDGE('',*,*,#130,.F.);
#774=ORIENTED_EDGE('',*,*,#101,.F.);
#775=ORIENTED_EDGE('',*,*,#70,.F.);
#776=EDGE_LOOP('',(#772,#773,#774,#775));
#777=FACE_BOUND('',#776,.T.);
#778=ADVANCED_FACE('F305',(#499,#533,#567,#601,#635,#669,#703,#737,#771,#777),#465,.T.);
#779=CARTESIAN_POINT('',(125.,375.,0.));
#780=DIRECTION('',(1.,0.,0.));
#781=DIRECTION('',(0.,0.,-1.));
#782=AXIS2_PLACEMENT_3D('',#779,#780,#781);
#783=PLANE('',#782);
#784=ORIENTED_EDGE('',*,*,#436,.T.);
#785=DIRECTION('',(0.,0.,1.));
#786=VECTOR('',#785,1.);
#787=CARTESIAN_POINT('',(125.,400.,0.));
#788=LINE('',#787,#786);
#789=EDGE_CURVE('E564',#745,#425,#788,.T.);
#790=ORIENTED_EDGE('',*,*,#789,.F.);
#791=ORIENTED_EDGE('',*,*,#746,.F.);
#792=DIRECTION('',(0.,0.,1.));
#793=VECTOR('',#792,1.);
#794=CARTESIAN_POINT('',(125.,375.,0.));
#795=LINE('',#794,#793);
#796=EDGE_CURVE('E574',#743,#435,#795,.T.);
#797=ORIENTED_EDGE('',*,*,#796,.T.);
#798=EDGE_LOOP('',(#784,#790,#791,#797));
#799=FACE_BOUND('',#798,.T.);
#800=ADVANCED_FACE('F637',(#799),#783,.F.);
#801=CARTESIAN_POINT('',(75.,375.,0.));
#802=DIRECTION('',(0.,-1.,0.));
#803=DIRECTION('',(0.,0.,-1.));
#804=AXIS2_PLACEMENT_3D('',#801,#802,#803);
#805=PLANE('',#804);
#806=ORIENTED_EDGE('',*,*,#444,.T.);
#807=ORIENTED_EDGE('',*,*,#796,.F.);
#808=ORIENTED_EDGE('',*,*,#768,.F.);
#809=DIRECTION('',(0.,0.,1.));
#810=VECTOR('',#809,1.);
#811=CARTESIAN_POINT('',(75.,375.,0.));
#812=LINE('',#811,#810);
#813=EDGE_CURVE('E577',#761,#443,#812,.T.);
#814=ORIENTED_EDGE('',*,*,#813,.T.);
#815=EDGE_LOOP('',(#806,#807,#808,#814));
#816=FACE_BOUND('',#815,.T.);
#817=ADVANCED_FACE('F643',(#816),#805,.F.);
#818=CARTESIAN_POINT('',(75.,375.,0.));
#819=DIRECTION('',(-1.,0.,0.));
#820=DIRECTION('',(0.,0.,1.));
#821=AXIS2_PLACEMENT_3D('',#818,#819,#820);
#822=PLANE('',#821);
#823=ORIENTED_EDGE('',*,*,#450,.T.);
#824=ORIENTED_EDGE('',*,*,#813,.F.);
#825=ORIENTED_EDGE('',*,*,#762,.F.);
#826=DIRECTION('',(0.,0.,1.));
#827=VECTOR('',#826,1.);
#828=CARTESIAN_POINT('',(75.,400.,0.));
#829=LINE('',#828,#827);
#830=EDGE_CURVE('E579',#753,#427,#829,.T.);
#831=ORIENTED_EDGE('',*,*,#830,.T.);
#832=EDGE_LOOP('',(#823,#824,#825,#831));
#833=FACE_BOUND('',#832,.T.);
#834=ADVANCED_FACE('F649',(#833),#822,.F.);
#835=CARTESIAN_POINT('',(75.,400.,0.));
#836=DIRECTION('',(0.,1.,0.));
#837=DIRECTION('',(0.,0.,1.));
#838=AXIS2_PLACEMENT_3D('',#835,#836,#837);
#839=PLANE('',#838);
#840=ORIENTED_EDGE('',*,*,#428,.T.);
#841=ORIENTED_EDGE('',*,*,#830,.F.);
#842=ORIENTED_EDGE('',*,*,#754,.F.);
#843=ORIENTED_EDGE('',*,*,#789,.T.);
#844=EDGE_LOOP('',(#840,#841,#842,#843));
#845=FACE_BOUND('',#844,.T.);
#846=ADVANCED_FACE('F645',(#845),#839,.F.);
#847=CARTESIAN_POINT('',(275.,375.,0.));
#848=DIRECTION('',(1.,0.,0.));
#849=DIRECTION('',(0.,0.,-1.));
#850=AXIS2_PLACEMENT_3D('',#847,#848,#849);
#851=PLANE('',#850);
#852=ORIENTED_EDGE('',*,*,#402,.T.);
#853=DIRECTION('',(0.,0.,1.));
#854=VECTOR('',#853,1.);
#855=CARTESIAN_POINT('',(275.,400.,0.));
#856=LINE('',#855,#854);
#857=EDGE_CURVE('E532',#711,#391,#856,.T.);
#858=ORIENTED_EDGE('',*,*,#857,.F.);
#859=ORIENTED_EDGE('',*,*,#712,.F.);
#860=DIRECTION('',(0.,0.,1.));
#861=VECTOR('',#860,1.);
#862=CARTESIAN_POINT('',(275.,375.,0.));
#863=LINE('',#862,#861);
#864=EDGE_CURVE('E542',#709,#401,#863,.T.);
#865=ORIENTED_EDGE('',*,*,#864,.T.);
#866=EDGE_LOOP('',(#852,#858,#859,#865));
#867=FACE_BOUND('',#866,.T.);
#868=ADVANCED_FACE('F648',(#867),#851,.F.);
#869=CARTESIAN_POINT('',(225.,375.,0.));
#870=DIRECTION('',(0.,-1.,0.));
#871=DIRECTION('',(0.,0.,-1.));
#872=AXIS2_PLACEMENT_3D('',#869,#870,#871);
#873=PLANE('',#872);
#874=ORIENTED_EDGE('',*,*,#410,.T.);
#875=ORIENTED_EDGE('',*,*,#864,.F.);
#876=ORIENTED_EDGE('',*,*,#734,.F.);
#877=DIRECTION('',(0.,0.,1.));
#878=VECTOR('',#877,1.);
#879=CARTESIAN_POINT('',(225.,375.,0.));
#880=LINE('',#879,#878);
#881=EDGE_CURVE('E545',#727,#409,#880,.T.);
#882=ORIENTED_EDGE('',*,*,#881,.T.);
#883=EDGE_LOOP('',(#874,#875,#876,#882));
#884=FACE_BOUND('',#883,.T.);
#885=ADVANCED_FACE('F659',(#884),#873,.F.);
#886=CARTESIAN_POINT('',(225.,375.,0.));
#887=DIRECTION('',(-1.,0.,0.));
#888=DIRECTION('',(0.,0.,1.));
#889=AXIS2_PLACEMENT_3D('',#886,#887,#888);
#890=PLANE('',#889);
#891=ORIENTED_EDGE('',*,*,#416,.T.);
#892=ORIENTED_EDGE('',*,*,#881,.F.);
#893=ORIENTED_EDGE('',*,*,#728,.F.);
#894=DIRECTION('',(0.,0.,1.));
#895=VECTOR('',#894,1.);
#896=CARTESIAN_POINT('',(225.,400.,0.));
#897=LINE('',#896,#895);
#898=EDGE_CURVE('E547',#719,#393,#897,.T.);
#899=ORIENTED_EDGE('',*,*,#898,.T.);
#900=EDGE_LOOP('',(#891,#892,#893,#899));
#901=FACE_BOUND('',#900,.T.);
#902=ADVANCED_FACE('F665',(#901),#890,.F.);
#903=CARTESIAN_POINT('',(225.,400.,0.));
#904=DIRECTION('',(0.,1.,0.));
#905=DIRECTION('',(0.,0.,1.));
#906=AXIS2_PLACEMENT_3D('',#903,#904,#905);
#907=PLANE('',#906);
#908=ORIENTED_EDGE('',*,*,#394,.T.);
#909=ORIENTED_EDGE('',*,*,#898,.F.);
#910=ORIENTED_EDGE('',*,*,#720,.F.);
#911=ORIENTED_EDGE('',*,*,#857,.T.);
#912=EDGE_LOOP('',(#908,#909,#910,#911));
#913=FACE_BOUND('',#912,.T.);
#914=ADVANCED_FACE('F661',(#913),#907,.F.);
#915=CARTESIAN_POINT('',(275.,300.,0.));
#916=DIRECTION('',(1.,0.,0.));
#917=DIRECTION('',(0.,0.,-1.));
#918=AXIS2_PLACEMENT_3D('',#915,#916,#917);
#919=PLANE('',#918);
#920=ORIENTED_EDGE('',*,*,#368,.T.);
#921=DIRECTION('',(0.,0.,1.));
#922=VECTOR('',#921,1.);
#923=CARTESIAN_POINT('',(275.,325.,0.));
#924=LINE('',#923,#922);
#925=EDGE_CURVE('E500',#677,#357,#924,.T.);
#926=ORIENTED_EDGE('',*,*,#925,.F.);
#927=ORIENTED_EDGE('',*,*,#678,.F.);
#928=DIRECTION('',(0.,0.,1.));
#929=VECTOR('',#928,1.);
#930=CARTESIAN_POINT('',(275.,300.,0.));
#931=LINE('',#930,#929);
#932=EDGE_CURVE('E510',#675,#367,#931,.T.);
#933=ORIENTED_EDGE('',*,*,#932,.T.);
#934=EDGE_LOOP('',(#920,#926,#927,#933));
#935=FACE_BOUND('',#934,.T.);
#936=ADVANCED_FACE('F664',(#935),#919,.F.);
#937=CARTESIAN_POINT('',(225.,300.,0.));
#938=DIRECTION('',(0.,-1.,0.));
#939=DIRECTION('',(0.,0.,-1.));
#940=AXIS2_PLACEMENT_3D('',#937,#938,#939);
#941=PLANE('',#940);
#942=ORIENTED_EDGE('',*,*,#376,.T.);
#943=ORIENTED_EDGE('',*,*,#932,.F.);
#944=ORIENTED_EDGE('',*,*,#700,.F.);
#945=DIRECTION('',(0.,0.,1.));
#946=VECTOR('',#945,1.);
#947=CARTESIAN_POINT('',(225.,300.,0.));
#948=LINE('',#947,#946);
#949=EDGE_CURVE('E513',#693,#375,#948,.T.);
#950=ORIENTED_EDGE('',*,*,#949,.T.);
#951=EDGE_LOOP('',(#942,#943,#944,#950));
#952=FACE_BOUND('',#951,.T.);
#953=ADVANCED_FACE('F675',(#952),#941,.F.);
#954=CARTESIAN_POINT('',(225.,300.,0.));
#955=DIRECTION('',(-1.,0.,0.));
#956=DIRECTION('',(0.,0.,1.));
#957=AXIS2_PLACEMENT_3D('',#954,#955,#956);
#958=PLANE('',#957);
#959=ORIENTED_EDGE('',*,*,#382,.T.);
#960=ORIENTED_EDGE('',*,*,#949,.F.);
#961=ORIENTED_EDGE('',*,*,#694,.F.);
#962=DIRECTION('',(0.,0.,1.));
#963=VECTOR('',#962,1.);
#964=CARTESIAN_POINT('',(225.,325.,0.));
#965=LINE('',#964,#963);
#966=EDGE_CURVE('E515',#685,#359,#965,.T.);
#967=ORIENTED_EDGE('',*,*,#966,.T.);
#968=EDGE_LOOP('',(#959,#960,#961,#967));
#969=FACE_BOUND('',#968,.T.);
#970=ADVANCED_FACE('F681',(#969),#958,.F.);
#971=CARTESIAN_POINT('',(225.,325.,0.));
#972=DIRECTION('',(0.,1.,0.));
#973=DIRECTION('',(0.,0.,1.));
#974=AXIS2_PLACEMENT_3D('',#971,#972,#973);
#975=PLANE('',#974);
#976=ORIENTED_EDGE('',*,*,#360,.T.);
#977=ORIENTED_EDGE('',*,*,#966,.F.);
#978=ORIENTED_EDGE('',*,*,#686,.F.);
#979=ORIENTED_EDGE('',*,*,#925,.T.);
#980=EDGE_LOOP('',(#976,#977,#978,#979));
#981=FACE_BOUND('',#980,.T.);
#982=ADVANCED_FACE('F677',(#981),#975,.F.);
#983=CARTESIAN_POINT('',(125.,300.,0.));
#984=DIRECTION('',(1.,0.,0.));
#985=DIRECTION('',(0.,0.,-1.));
#986=AXIS2_PLACEMENT_3D('',#983,#984,#985);
#987=PLANE('',#986);
#988=ORIENTED_EDGE('',*,*,#334,.T.);
#989=DIRECTION('',(0.,0.,1.));
#990=VECTOR('',#989,1.);
#991=CARTESIAN_POINT('',(125.,325.,0.));
#992=LINE('',#991,#990);
#993=EDGE_CURVE('E468',#643,#323,#992,.T.);
#994=ORIENTED_EDGE('',*,*,#993,.F.);
#995=ORIENTED_EDGE('',*,*,#644,.F.);
#996=DIRECTION('',(0.,0.,1.));
#997=VECTOR('',#996,1.);
#998=CARTESIAN_POINT('',(125.,300.,0.));
#999=LINE('',#998,#997);
#1000=EDGE_CURVE('E478',#641,#333,#999,.T.);
#1001=ORIENTED_EDGE('',*,*,#1000,.T.);
#1002=EDGE_LOOP('',(#988,#994,#995,#1001));
#1003=FACE_BOUND('',#1002,.T.);
#1004=ADVANCED_FACE('F680',(#1003),#987,.F.);
#1005=CARTESIAN_POINT('',(75.,300.,0.));
#1006=DIRECTION('',(0.,-1.,0.));
#1007=DIRECTION('',(0.,0.,-1.));
#1008=AXIS2_PLACEMENT_3D('',#1005,#1006,#1007);
#1009=PLANE('',#1008);
#1010=ORIENTED_EDGE('',*,*,#342,.T.);
#1011=ORIENTED_EDGE('',*,*,#1000,.F.);
#1012=ORIENTED_EDGE('',*,*,#666,.F.);
#1013=DIRECTION('',(0.,0.,1.));
#1014=VECTOR('',#1013,1.);
#1015=CARTESIAN_POINT('',(75.,300.,0.));
#1016=LINE('',#1015,#1014);
#1017=EDGE_CURVE('E481',#659,#341,#1016,.T.);
#1018=ORIENTED_EDGE('',*,*,#1017,.T.);
#1019=EDGE_LOOP('',(#1010,#1011,#1012,#1018));
#1020=FACE_BOUND('',#1019,.T.);
#1021=ADVANCED_FACE('F691',(#1020),#1009,.F.);
#1022=CARTESIAN_POINT('',(75.,300.,0.));
#1023=DIRECTION('',(-1.,0.,0.));
#1024=DIRECTION('',(0.,0.,1.));
#1025=AXIS2_PLACEMENT_3D('',#1022,#1023,#1024);
#1026=PLANE('',#1025);
#1027=ORIENTED_EDGE('',*,*,#348,.T.);
#1028=ORIENTED_EDGE('',*,*,#1017,.F.);
#1029=ORIENTED_EDGE('',*,*,#660,.F.);
#1030=DIRECTION('',(0.,0.,1.));
#1031=VECTOR('',#1030,1.);
#1032=CARTESIAN_POINT('',(75.,325.,0.));
#1033=LINE('',#1032,#1031);
#1034=EDGE_CURVE('E483',#651,#325,#1033,.T.);
#1035=ORIENTED_EDGE('',*,*,#1034,.T.);
#1036=EDGE_LOOP('',(#1027,#1028,#1029,#1035));
#1037=FACE_BOUND('',#1036,.T.);
#1038=ADVANCED_FACE('F697',(#1037),#1026,.F.);
#1039=CARTESIAN_POINT('',(75.,325.,0.));
#1040=DIRECTION('',(0.,1.,0.));
#1041=DIRECTION('',(0.,0.,1.));
#1042=AXIS2_PLACEMENT_3D('',#1039,#1040,#1041);
#1043=PLANE('',#1042);
#1044=ORIENTED_EDGE('',*,*,#326,.T.);
#1045=ORIENTED_EDGE('',*,*,#1034,.F.);
#1046=ORIENTED_EDGE('',*,*,#652,.F.);
#1047=ORIENTED_EDGE('',*,*,#993,.T.);
#1048=EDGE_LOOP('',(#1044,#1045,#1046,#1047));
#1049=FACE_BOUND('',#1048,.T.);
#1050=ADVANCED_FACE('F693',(#1049),#1043,.F.);
#1051=CARTESIAN_POINT('',(125.,225.,0.));
#1052=DIRECTION('',(1.,0.,0.));
#1053=DIRECTION('',(0.,0.,-1.));
#1054=AXIS2_PLACEMENT_3D('',#1051,#1052,#1053);
#1055=PLANE('',#1054);
#1056=ORIENTED_EDGE('',*,*,#300,.T.);
#1057=DIRECTION('',(0.,0.,1.));
#1058=VECTOR('',#1057,1.);
#1059=CARTESIAN_POINT('',(125.,250.,0.));
#1060=LINE('',#1059,#1058);
#1061=EDGE_CURVE('E436',#609,#289,#1060,.T.);
#1062=ORIENTED_EDGE('',*,*,#1061,.F.);
#1063=ORIENTED_EDGE('',*,*,#610,.F.);
#1064=DIRECTION('',(0.,0.,1.));
#1065=VECTOR('',#1064,1.);
#1066=CARTESIAN_POINT('',(125.,225.,0.));
#1067=LINE('',#1066,#1065);
#1068=EDGE_CURVE('E446',#607,#299,#1067,.T.);
#1069=ORIENTED_EDGE('',*,*,#1068,.T.);
#1070=EDGE_LOOP('',(#1056,#1062,#1063,#1069));
#1071=FACE_BOUND('',#1070,.T.);
#1072=ADVANCED_FACE('F696',(#1071),#1055,.F.);
#1073=CARTESIAN_POINT('',(75.0000000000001,225.,0.));
#1074=DIRECTION('',(0.,-1.,0.));
#1075=DIRECTION('',(0.,0.,-1.));
#1076=AXIS2_PLACEMENT_3D('',#1073,#1074,#1075);
#1077=PLANE('',#1076);
#1078=ORIENTED_EDGE('',*,*,#308,.T.);
#1079=ORIENTED_EDGE('',*,*,#1068,.F.);
#1080=ORIENTED_EDGE('',*,*,#632,.F.);
#1081=DIRECTION('',(0.,0.,1.));
#1082=VECTOR('',#1081,1.);
#1083=CARTESIAN_POINT('',(75.0000000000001,225.,0.));
#1084=LINE('',#1083,#1082);
#1085=EDGE_CURVE('E449',#625,#307,#1084,.T.);
#1086=ORIENTED_EDGE('',*,*,#1085,.T.);
#1087=EDGE_LOOP('',(#1078,#1079,#1080,#1086));
#1088=FACE_BOUND('',#1087,.T.);
#1089=ADVANCED_FACE('F707',(#1088),#1077,.F.);
#1090=CARTESIAN_POINT('',(75.0000000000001,225.,0.));
#1091=DIRECTION('',(-1.,0.,0.));
#1092=DIRECTION('',(0.,0.,1.));
#1093=AXIS2_PLACEMENT_3D('',#1090,#1091,#1092);
#1094=PLANE('',#1093);
#1095=ORIENTED_EDGE('',*,*,#314,.T.);
#1096=ORIENTED_EDGE('',*,*,#1085,.F.);
#1097=ORIENTED_EDGE('',*,*,#626,.F.);
#1098=DIRECTION('',(0.,0.,1.));
#1099=VECTOR('',#1098,1.);
#1100=CARTESIAN_POINT('',(75.0000000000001,250.,0.));
#1101=LINE('',#1100,#1099);
#1102=EDGE_CURVE('E451',#617,#291,#1101,.T.);
#1103=ORIENTED_EDGE('',*,*,#1102,.T.);
#1104=EDGE_LOOP('',(#1095,#1096,#1097,#1103));
#1105=FACE_BOUND('',#1104,.T.);
#1106=ADVANCED_FACE('F713',(#1105),#1094,.F.);
#1107=CARTESIAN_POINT('',(75.0000000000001,250.,0.));
#1108=DIRECTION('',(0.,1.,0.));
#1109=DIRECTION('',(0.,0.,1.));
#1110=AXIS2_PLACEMENT_3D('',#1107,#1108,#1109);
#1111=PLANE('',#1110);
#1112=ORIENTED_EDGE('',*,*,#292,.T.);
#1113=ORIENTED_EDGE('',*,*,#1102,.F.);
#1114=ORIENTED_EDGE('',*,*,#618,.F.);
#1115=ORIENTED_EDGE('',*,*,#1061,.T.);
#1116=EDGE_LOOP('',(#1112,#1113,#1114,#1115));
#1117=FACE_BOUND('',#1116,.T.);
#1118=ADVANCED_FACE('F709',(#1117),#1111,.F.);
#1119=CARTESIAN_POINT('',(275.,225.,0.));
#1120=DIRECTION('',(1.,0.,0.));
#1121=DIRECTION('',(0.,0.,-1.));
#1122=AXIS2_PLACEMENT_3D('',#1119,#1120,#1121);
#1123=PLANE('',#1122);
#1124=ORIENTED_EDGE('',*,*,#266,.T.);
#1125=DIRECTION('',(0.,0.,1.));
#1126=VECTOR('',#1125,1.);
#1127=CARTESIAN_POINT('',(275.,250.,0.));
#1128=LINE('',#1127,#1126);
#1129=EDGE_CURVE('E404',#575,#255,#1128,.T.);
#1130=ORIENTED_EDGE('',*,*,#1129,.F.);
#1131=ORIENTED_EDGE('',*,*,#576,.F.);
#1132=DIRECTION('',(0.,0.,1.));
#1133=VECTOR('',#1132,1.);
#1134=CARTESIAN_POINT('',(275.,225.,0.));
#1135=LINE('',#1134,#1133);
#1136=EDGE_CURVE('E414',#573,#265,#1135,.T.);
#1137=ORIENTED_EDGE('',*,*,#1136,.T.);
#1138=EDGE_LOOP('',(#1124,#1130,#1131,#1137));
#1139=FACE_BOUND('',#1138,.T.);
#1140=ADVANCED_FACE('F712',(#1139),#1123,.F.);
#1141=CARTESIAN_POINT('',(225.,225.,0.));
#1142=DIRECTION('',(0.,-1.,0.));
#1143=DIRECTION('',(0.,0.,-1.));
#1144=AXIS2_PLACEMENT_3D('',#1141,#1142,#1143);
#1145=PLANE('',#1144);
#1146=ORIENTED_EDGE('',*,*,#274,.T.);
#1147=ORIENTED_EDGE('',*,*,#1136,.F.);
#1148=ORIENTED_EDGE('',*,*,#598,.F.);
#1149=DIRECTION('',(0.,0.,1.));
#1150=VECTOR('',#1149,1.);
#1151=CARTESIAN_POINT('',(225.,225.,0.));
#1152=LINE('',#1151,#1150);
#1153=EDGE_CURVE('E417',#591,#273,#1152,.T.);
#1154=ORIENTED_EDGE('',*,*,#1153,.T.);
#1155=EDGE_LOOP('',(#1146,#1147,#1148,#1154));
#1156=FACE_BOUND('',#1155,.T.);
#1157=ADVANCED_FACE('F723',(#1156),#1145,.F.);
#1158=CARTESIAN_POINT('',(225.,225.,0.));
#1159=DIRECTION('',(-1.,0.,0.));
#1160=DIRECTION('',(0.,0.,1.));
#1161=AXIS2_PLACEMENT_3D('',#1158,#1159,#1160);
#1162=PLANE('',#1161);
#1163=ORIENTED_EDGE('',*,*,#280,.T.);
#1164=ORIENTED_EDGE('',*,*,#1153,.F.);
#1165=ORIENTED_EDGE('',*,*,#592,.F.);
#1166=DIRECTION('',(0.,0.,1.));
#1167=VECTOR('',#1166,1.);
#1168=CARTESIAN_POINT('',(225.,250.,0.));
#1169=LINE('',#1168,#1167);
#1170=EDGE_CURVE('E419',#583,#257,#1169,.T.);
#1171=ORIENTED_EDGE('',*,*,#1170,.T.);
#1172=EDGE_LOOP('',(#1163,#1164,#1165,#1171));
#1173=FACE_BOUND('',#1172,.T.);
#1174=ADVANCED_FACE('F729',(#1173),#1162,.F.);
#1175=CARTESIAN_POINT('',(225.,250.,0.));
#1176=DIRECTION('',(0.,1.,0.));
#1177=DIRECTION('',(0.,0.,1.));
#1178=AXIS2_PLACEMENT_3D('',#1175,#1176,#1177);
#1179=PLANE('',#1178);
#1180=ORIENTED_EDGE('',*,*,#258,.T.);
#1181=ORIENTED_EDGE('',*,*,#1170,.F.);
#1182=ORIENTED_EDGE('',*,*,#584,.F.);
#1183=ORIENTED_EDGE('',*,*,#1129,.T.);
#1184=EDGE_LOOP('',(#1180,#1181,#1182,#1183));
#1185=FACE_BOUND('',#1184,.T.);
#1186=ADVANCED_FACE('F725',(#1185),#1179,.F.);
#1187=CARTESIAN_POINT('',(200.,150.,0.));
#1188=DIRECTION('',(1.,0.,0.));
#1189=DIRECTION('',(0.,0.,-1.));
#1190=AXIS2_PLACEMENT_3D('',#1187,#1188,#1189);
#1191=PLANE('',#1190);
#1192=ORIENTED_EDGE('',*,*,#232,.T.);
#1193=DIRECTION('',(0.,0.,1.));
#1194=VECTOR('',#1193,1.);
#1195=CARTESIAN_POINT('',(200.,175.,0.));
#1196=LINE('',#1195,#1194);
#1197=EDGE_CURVE('E372',#541,#221,#1196,.T.);
#1198=ORIENTED_EDGE('',*,*,#1197,.F.);
#1199=ORIENTED_EDGE('',*,*,#542,.F.);
#1200=DIRECTION('',(0.,0.,1.));
#1201=VECTOR('',#1200,1.);
#1202=CARTESIAN_POINT('',(200.,150.,0.));
#1203=LINE('',#1202,#1201);
#1204=EDGE_CURVE('E382',#539,#231,#1203,.T.);
#1205=ORIENTED_EDGE('',*,*,#1204,.T.);
#1206=EDGE_LOOP('',(#1192,#1198,#1199,#1205));
#1207=FACE_BOUND('',#1206,.T.);
#1208=ADVANCED_FACE('F728',(#1207),#1191,.F.);
#1209=CARTESIAN_POINT('',(150.,150.,0.));
#1210=DIRECTION('',(0.,-1.,0.));
#1211=DIRECTION('',(0.,0.,-1.));
#1212=AXIS2_PLACEMENT_3D('',#1209,#1210,#1211);
#1213=PLANE('',#1212);
#1214=ORIENTED_EDGE('',*,*,#240,.T.);
#1215=ORIENTED_EDGE('',*,*,#1204,.F.);
#1216=ORIENTED_EDGE('',*,*,#564,.F.);
#1217=DIRECTION('',(0.,0.,1.));
#1218=VECTOR('',#1217,1.);
#1219=CARTESIAN_POINT('',(150.,150.,0.));
#1220=LINE('',#1219,#1218);
#1221=EDGE_CURVE('E385',#557,#239,#1220,.T.);
#1222=ORIENTED_EDGE('',*,*,#1221,.T.);
#1223=EDGE_LOOP('',(#1214,#1215,#1216,#1222));
#1224=FACE_BOUND('',#1223,.T.);
#1225=ADVANCED_FACE('F739',(#1224),#1213,.F.);
#1226=CARTESIAN_POINT('',(150.,150.,0.));
#1227=DIRECTION('',(-1.,0.,0.));
#1228=DIRECTION('',(0.,0.,1.));
#1229=AXIS2_PLACEMENT_3D('',#1226,#1227,#1228);
#1230=PLANE('',#1229);
#1231=ORIENTED_EDGE('',*,*,#246,.T.);
#1232=ORIENTED_EDGE('',*,*,#1221,.F.);
#1233=ORIENTED_EDGE('',*,*,#558,.F.);
#1234=DIRECTION('',(0.,0.,1.));
#1235=VECTOR('',#1234,1.);
#1236=CARTESIAN_POINT('',(150.,175.,0.));
#1237=LINE('',#1236,#1235);
#1238=EDGE_CURVE('E387',#549,#223,#1237,.T.);
#1239=ORIENTED_EDGE('',*,*,#1238,.T.);
#1240=EDGE_LOOP('',(#1231,#1232,#1233,#1239));
#1241=FACE_BOUND('',#1240,.T.);
#1242=ADVANCED_FACE('F745',(#1241),#1230,.F.);
#1243=CARTESIAN_POINT('',(150.,175.,0.));
#1244=DIRECTION('',(0.,1.,0.));
#1245=DIRECTION('',(0.,0.,1.));
#1246=AXIS2_PLACEMENT_3D('',#1243,#1244,#1245);
#1247=PLANE('',#1246);
#1248=ORIENTED_EDGE('',*,*,#224,.T.);
#1249=ORIENTED_EDGE('',*,*,#1238,.F.);
#1250=ORIENTED_EDGE('',*,*,#550,.F.);
#1251=ORIENTED_EDGE('',*,*,#1197,.T.);
#1252=EDGE_LOOP('',(#1248,#1249,#1250,#1251));
#1253=FACE_BOUND('',#1252,.T.);
#1254=ADVANCED_FACE('F741',(#1253),#1247,.F.);
#1255=CARTESIAN_POINT('',(125.,49.9999999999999,0.));
#1256=DIRECTION('',(1.,0.,0.));
#1257=DIRECTION('',(0.,0.,-1.));
#1258=AXIS2_PLACEMENT_3D('',#1255,#1256,#1257);
#1259=PLANE('',#1258);
#1260=ORIENTED_EDGE('',*,*,#198,.T.);
#1261=DIRECTION('',(0.,0.,1.));
#1262=VECTOR('',#1261,1.);
#1263=CARTESIAN_POINT('',(125.,75.,0.));
#1264=LINE('',#1263,#1262);
#1265=EDGE_CURVE('E340',#507,#187,#1264,.T.);
#1266=ORIENTED_EDGE('',*,*,#1265,.F.);
#1267=ORIENTED_EDGE('',*,*,#508,.F.);
#1268=DIRECTION('',(0.,0.,1.));
#1269=VECTOR('',#1268,1.);
#1270=CARTESIAN_POINT('',(125.,49.9999999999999,0.));
#1271=LINE('',#1270,#1269);
#1272=EDGE_CURVE('E350',#505,#197,#1271,.T.);
#1273=ORIENTED_EDGE('',*,*,#1272,.T.);
#1274=EDGE_LOOP('',(#1260,#1266,#1267,#1273));
#1275=FACE_BOUND('',#1274,.T.);
#1276=ADVANCED_FACE('F744',(#1275),#1259,.F.);
#1277=CARTESIAN_POINT('',(75.0000000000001,49.9999999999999,0.));
#1278=DIRECTION('',(0.,-1.,0.));
#1279=DIRECTION('',(0.,0.,-1.));
#1280=AXIS2_PLACEMENT_3D('',#1277,#1278,#1279);
#1281=PLANE('',#1280);
#1282=ORIENTED_EDGE('',*,*,#206,.T.);
#1283=ORIENTED_EDGE('',*,*,#1272,.F.);
#1284=ORIENTED_EDGE('',*,*,#530,.F.);
#1285=DIRECTION('',(0.,0.,1.));
#1286=VECTOR('',#1285,1.);
#1287=CARTESIAN_POINT('',(75.0000000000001,49.9999999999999,0.));
#1288=LINE('',#1287,#1286);
#1289=EDGE_CURVE('E353',#523,#205,#1288,.T.);
#1290=ORIENTED_EDGE('',*,*,#1289,.T.);
#1291=EDGE_LOOP('',(#1282,#1283,#1284,#1290));
#1292=FACE_BOUND('',#1291,.T.);
#1293=ADVANCED_FACE('F755',(#1292),#1281,.F.);
#1294=CARTESIAN_POINT('',(75.0000000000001,49.9999999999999,0.));
#1295=DIRECTION('',(-1.,0.,0.));
#1296=DIRECTION('',(0.,0.,1.));
#1297=AXIS2_PLACEMENT_3D('',#1294,#1295,#1296);
#1298=PLANE('',#1297);
#1299=ORIENTED_EDGE('',*,*,#212,.T.);
#1300=ORIENTED_EDGE('',*,*,#1289,.F.);
#1301=ORIENTED_EDGE('',*,*,#524,.F.);
#1302=DIRECTION('',(0.,0.,1.));
#1303=VECTOR('',#1302,1.);
#1304=CARTESIAN_POINT('',(75.0000000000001,75.,0.));
#1305=LINE('',#1304,#1303);
#1306=EDGE_CURVE('E355',#515,#189,#1305,.T.);
#1307=ORIENTED_EDGE('',*,*,#1306,.T.);
#1308=EDGE_LOOP('',(#1299,#1300,#1301,#1307));
#1309=FACE_BOUND('',#1308,.T.);
#1310=ADVANCED_FACE('F760',(#1309),#1298,.F.);
#1311=CARTESIAN_POINT('',(75.0000000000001,75.,0.));
#1312=DIRECTION('',(0.,1.,0.));
#1313=DIRECTION('',(0.,0.,1.));
#1314=AXIS2_PLACEMENT_3D('',#1311,#1312,#1313);
#1315=PLANE('',#1314);
#1316=ORIENTED_EDGE('',*,*,#190,.T.);
#1317=ORIENTED_EDGE('',*,*,#1306,.F.);
#1318=ORIENTED_EDGE('',*,*,#516,.F.);
#1319=ORIENTED_EDGE('',*,*,#1265,.T.);
#1320=EDGE_LOOP('',(#1316,#1317,#1318,#1319));
#1321=FACE_BOUND('',#1320,.T.);
#1322=ADVANCED_FACE('F757',(#1321),#1315,.F.);
#1323=CARTESIAN_POINT('',(275.,49.9999999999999,0.));
#1324=DIRECTION('',(1.,0.,0.));
#1325=DIRECTION('',(0.,0.,-1.));
#1326=AXIS2_PLACEMENT_3D('',#1323,#1324,#1325);
#1327=PLANE('',#1326);
#1328=ORIENTED_EDGE('',*,*,#164,.T.);
#1329=DIRECTION('',(0.,0.,1.));
#1330=VECTOR('',#1329,1.);
#1331=CARTESIAN_POINT('',(275.,75.,0.));
#1332=LINE('',#1331,#1330);
#1333=EDGE_CURVE('E288',#473,#153,#1332,.T.);
#1334=ORIENTED_EDGE('',*,*,#1333,.F.);
#1335=ORIENTED_EDGE('',*,*,#474,.F.);
#1336=DIRECTION('',(0.,0.,1.));
#1337=VECTOR('',#1336,1.);
#1338=CARTESIAN_POINT('',(275.,49.9999999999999,0.));
#1339=LINE('',#1338,#1337);
#1340=EDGE_CURVE('E321',#471,#163,#1339,.T.);
#1341=ORIENTED_EDGE('',*,*,#1340,.T.);
#1342=EDGE_LOOP('',(#1328,#1334,#1335,#1341));
#1343=FACE_BOUND('',#1342,.T.);
#1344=ADVANCED_FACE('F290',(#1343),#1327,.F.);
#1345=CARTESIAN_POINT('',(225.,49.9999999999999,0.));
#1346=DIRECTION('',(0.,-1.,0.));
#1347=DIRECTION('',(0.,0.,-1.));
#1348=AXIS2_PLACEMENT_3D('',#1345,#1346,#1347);
#1349=PLANE('',#1348);
#1350=ORIENTED_EDGE('',*,*,#172,.T.);
#1351=ORIENTED_EDGE('',*,*,#1340,.F.);
#1352=ORIENTED_EDGE('',*,*,#496,.F.);
#1353=DIRECTION('',(0.,0.,1.));
#1354=VECTOR('',#1353,1.);
#1355=CARTESIAN_POINT('',(225.,49.9999999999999,0.));
#1356=LINE('',#1355,#1354);
#1357=EDGE_CURVE('E324',#489,#171,#1356,.T.);
#1358=ORIENTED_EDGE('',*,*,#1357,.T.);
#1359=EDGE_LOOP('',(#1350,#1351,#1352,#1358));
#1360=FACE_BOUND('',#1359,.T.);
#1361=ADVANCED_FACE('F770',(#1360),#1349,.F.);
#1362=CARTESIAN_POINT('',(225.,49.9999999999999,0.));
#1363=DIRECTION('',(-1.,0.,0.));
#1364=DIRECTION('',(0.,0.,1.));
#1365=AXIS2_PLACEMENT_3D('',#1362,#1363,#1364);
#1366=PLANE('',#1365);
#1367=ORIENTED_EDGE('',*,*,#178,.T.);
#1368=ORIENTED_EDGE('',*,*,#1357,.F.);
#1369=ORIENTED_EDGE('',*,*,#490,.F.);
#1370=DIRECTION('',(0.,0.,1.));
#1371=VECTOR('',#1370,1.);
#1372=CARTESIAN_POINT('',(225.,75.,0.));
#1373=LINE('',#1372,#1371);
#1374=EDGE_CURVE('E297',#481,#155,#1373,.T.);
#1375=ORIENTED_EDGE('',*,*,#1374,.T.);
#1376=EDGE_LOOP('',(#1367,#1368,#1369,#1375));
#1377=FACE_BOUND('',#1376,.T.);
#1378=ADVANCED_FACE('F773',(#1377),#1366,.F.);
#1379=CARTESIAN_POINT('',(225.,75.,0.));
#1380=DIRECTION('',(0.,1.,0.));
#1381=DIRECTION('',(0.,0.,1.));
#1382=AXIS2_PLACEMENT_3D('',#1379,#1380,#1381);
#1383=PLANE('',#1382);
#1384=ORIENTED_EDGE('',*,*,#156,.T.);
#1385=ORIENTED_EDGE('',*,*,#1374,.F.);
#1386=ORIENTED_EDGE('',*,*,#482,.F.);
#1387=ORIENTED_EDGE('',*,*,#1333,.T.);
#1388=EDGE_LOOP('',(#1384,#1385,#1386,#1387));
#1389=FACE_BOUND('',#1388,.T.);
#1390=ADVANCED_FACE('F302',(#1389),#1383,.F.);
#1391=CLOSED_SHELL('',(#58,#89,#120,#142,#460,#778,#800,#817,#834,#846,#868,#885,#902,#914,#936,
#953,#970,#982,#1004,#1021,#1038,#1050,#1072,#1089,#1106,#1118,#1140,#1157,#1174,#1186,#1208,
#1225,#1242,#1254,#1276,#1293,#1310,#1322,#1344,#1361,#1378,#1390));
#1392=MANIFOLD_SOLID_BREP('B2',#1391);
#1393=ADVANCED_BREP_SHAPE_REPRESENTATION('',(#18,#1392),#14);
#1394=SHAPE_DEFINITION_REPRESENTATION(#9,#1393);
ENDSEC;
END-ISO-10303-21;
